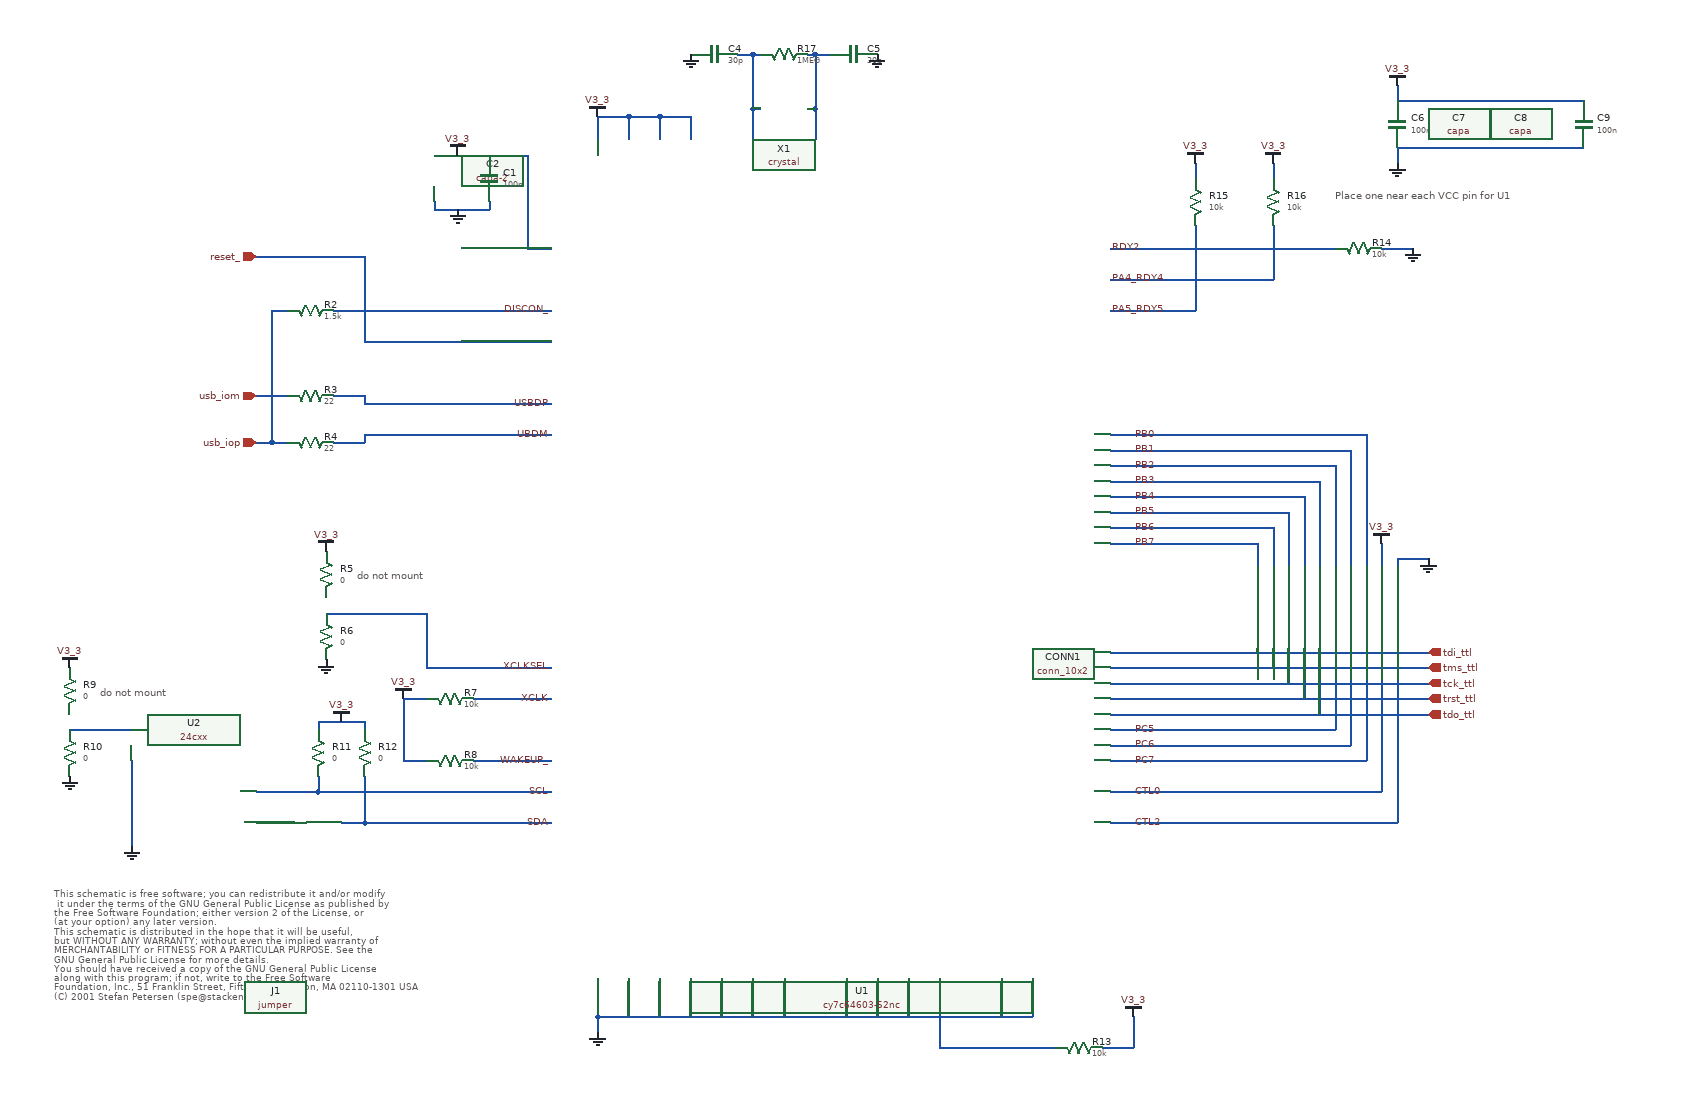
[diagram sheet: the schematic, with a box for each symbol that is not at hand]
v {xschem version=2.9.5_RC6 file_version=1.1}
G {}
V {}
S {}
E {}
T {do not mount} 410 -720 0 0 0.4 0.4 {}
T {do not mount} 80 -570 0 0 0.4 0.4 {}
T {This schematic is free software; you can redistribute it and/or modify
 it under the terms of the GNU General Public License as published by
the Free Software Foundation; either version 2 of the License, or
(at your option) any later version.
This schematic is distributed in the hope that it will be useful,
but WITHOUT ANY WARRANTY; without even the implied warranty of
MERCHANTABILITY or FITNESS FOR A PARTICULAR PURPOSE.  See the
GNU General Public License for more details.
You should have received a copy of the GNU General Public License
along with this program; if not, write to the Free Software
Foundation, Inc., 51 Franklin Street, Fifth Floor, Boston, MA 02110-1301 USA
(C) 2001 Stefan Petersen (spe@stacken.kth.se)
} 20 -310 0 0 0.3 0.3 {}
T {Place one near each VCC pin for U1} 1670 -1210 0 0 0.4 0.4 {}
N 840 -1300 840 -1270 {lab=V3_3}
N 800 -1300 840 -1300 {lab=V3_3}
N 720 -1300 720 -1270 {lab=V3_3}
N 760 -1300 760 -1270 {lab=V3_3}
N 800 -1300 800 -1270 {lab=V3_3}
N 1000 -1310 1000 -1270 {lab=#net1}
N 920 -1310 920 -1270 {lab=#net2}
N 990 -1310 1000 -1310 {lab=#net1}
N 920 -1310 930 -1310 {lab=#net2}
N 920 -1380 930 -1380 {lab=#net2}
N 1000 -1380 1020 -1380 {lab=#net1}
N 370 -660 500 -660 {lab=XCLKSEL}
N 500 -660 500 -590 {lab=XCLKSEL}
N 500 -590 660 -590 {lab=XCLKSEL}
N 560 -470 660 -470 {lab=WAKEUP_}
N 560 -550 660 -550 {lab=XCLK}
N 470 -550 500 -550 {lab=V3_3}
N 470 -550 470 -470 {lab=V3_3}
N 470 -470 500 -470 {lab=V3_3}
N 360 -430 660 -430 {lab=SCL}
N 120 -470 120 -360 {lab=GND}
N 40 -510 120 -510 {lab=#net3}
N 360 -520 360 -510 {lab=V3_3}
N 360 -520 420 -520 {lab=V3_3}
N 420 -520 420 -510 {lab=V3_3}
N 360 -450 360 -430 {lab=SCL}
N 420 -450 420 -390 {lab=SDA}
N 280 -390 330 -390 {lab=#net4}
N 420 -390 660 -390 {lab=SDA}
N 300 -880 320 -880 {lab=usb_iop}
N 280 -940 320 -940 {lab=usb_iom}
N 380 -880 420 -880 {lab=UBDM}
N 420 -890 420 -880 {lab=UBDM}
N 420 -890 660 -890 {lab=UBDM}
N 380 -940 420 -940 {lab=USBDP}
N 420 -940 420 -930 {lab=USBDP}
N 420 -930 660 -930 {lab=USBDP}
N 380 -1050 660 -1050 {lab=DISCON_}
N 300 -1050 320 -1050 {lab=usb_iop}
N 300 -1050 300 -880 {lab=usb_iop}
N 420 -1010 660 -1010 {lab=reset_}
N 420 -1120 420 -1010 {lab=reset_}
N 280 -1120 420 -1120 {lab=reset_}
N 630 -1130 660 -1130 {lab=V3_3}
N 630 -1250 630 -1130 {lab=V3_3}
N 510 -1250 630 -1250 {lab=V3_3}
N 510 -1190 510 -1180 {lab=GND}
N 510 -1180 580 -1180 {lab=GND}
N 580 -1190 580 -1180 {lab=GND}
N 1490 -1160 1490 -1050 {lab=PA5_RDY5}
N 1380 -1050 1490 -1050 {lab=PA5_RDY5}
N 1590 -1160 1590 -1090 {lab=PA4_RDY4}
N 1380 -1090 1590 -1090 {lab=PA4_RDY4}
N 1380 -1130 1670 -1130 {lab=RDY2}
N 1730 -1130 1770 -1130 {lab=GND}
N 1490 -1240 1490 -1220 {lab=V3_3}
N 1590 -1240 1590 -1220 {lab=V3_3}
N 1570 -750 1570 -720 {lab=PB7}
N 1380 -750 1570 -750 {lab=PB7}
N 1590 -770 1590 -720 {lab=PB6}
N 1380 -770 1590 -770 {lab=PB6}
N 1610 -790 1610 -720 {lab=PB5}
N 1380 -790 1610 -790 {lab=PB5}
N 1630 -810 1630 -720 {lab=PB4}
N 1380 -810 1630 -810 {lab=PB4}
N 1650 -830 1650 -720 {lab=PB3}
N 1380 -830 1650 -830 {lab=PB3}
N 1670 -850 1670 -720 {lab=PB2}
N 1380 -850 1670 -850 {lab=PB2}
N 1690 -870 1690 -720 {lab=PB1}
N 1380 -870 1690 -870 {lab=PB1}
N 1710 -890 1710 -720 {lab=PB0}
N 1380 -890 1710 -890 {lab=PB0}
N 1730 -750 1730 -720 {lab=V3_3}
N 1750 -730 1750 -720 {lab=GND}
N 1750 -730 1790 -730 {lab=GND}
N 1380 -610 1790 -610 {lab=tdi_ttl}
N 1380 -590 1790 -590 {lab=tms_ttl}
N 1380 -570 1790 -570 {lab=tck_ttl}
N 1380 -550 1790 -550 {lab=trst_ttl}
N 1380 -530 1790 -530 {lab=tdo_ttl}
N 1750 -660 1750 -390 {lab=CTL2}
N 1730 -660 1730 -430 {lab=CTL0}
N 1710 -660 1710 -470 {lab=PC7}
N 1690 -660 1690 -490 {lab=PC6}
N 720 -1300 760 -1300 {lab=V3_3}
N 760 -1300 800 -1300 {lab=V3_3}
N 1000 -1380 1000 -1310 {lab=#net1}
N 920 -1380 920 -1310 {lab=#net2}
N 280 -430 360 -430 {lab=SCL}
N 390 -390 420 -390 {lab=SDA}
N 280 -880 300 -880 {lab=usb_iop}
N 1380 -490 1690 -490 {lab=PC6}
N 1380 -470 1710 -470 {lab=PC7}
N 1380 -430 1730 -430 {lab=CTL0}
N 1380 -390 1750 -390 {lab=CTL2}
N 900 -1380 920 -1380 {lab=#net2}
N 990 -1380 1000 -1380 {lab=#net1}
N 1670 -660 1670 -510 {lab=PC5}
N 1380 -510 1670 -510 {lab=PC5}
N 1570 -660 1570 -610 {lab=tdi_ttl}
N 1590 -660 1590 -590 {lab=tms_ttl}
N 1610 -660 1610 -570 {lab=tck_ttl}
N 1630 -660 1630 -550 {lab=trst_ttl}
N 1650 -660 1650 -530 {lab=tdo_ttl}
N 1750 -1260 1990 -1260 {lab=GND}
N 1750 -1260 1750 -1240 {lab=GND}
N 1750 -1320 1990 -1320 {lab=V3_3}
N 1750 -1340 1750 -1320 {lab=V3_3}
N 720 -190 720 -140 {lab=GND}
N 760 -190 760 -140 {lab=GND}
N 800 -190 800 -140 {lab=GND}
N 840 -190 840 -140 {lab=GND}
N 880 -190 880 -140 {lab=GND}
N 920 -190 920 -140 {lab=GND}
N 960 -190 960 -140 {lab=GND}
N 1080 -190 1080 -140 {lab=GND}
N 1040 -190 1040 -140 {lab=GND}
N 1120 -190 1120 -140 {lab=GND}
N 1240 -190 1240 -140 {lab=GND}
N 1280 -190 1280 -140 {lab=GND}
N 720 -140 1280 -140 {lab=GND}
N 720 -140 720 -120 {lab=GND}
N 1160 -190 1160 -100 {lab=#net5}
N 1160 -100 1310 -100 {lab=#net5}
N 1370 -100 1410 -100 {lab=V3_3}
N 1410 -140 1410 -100 {lab=V3_3}
C {title.sym} 160 -30 0 0 {name=l1 author="Stefan Schippers"}
C {cy7c64603-52nc.sym} 1020 -630 0 0 {name=U1 device=cy7c64603-52nc footprint=cy7c64603_qfp}
C {vdd.sym} 720 -1300 0 0 {name=l2 lab=V3_3}
C {res.sym} 960 -1380 3 1 {name=R17
value=1MEG
footprint=1206
device=resistor
m=1}
C {crystal.sym} 960 -1310 1 0 {name=X1
value=12MHz
footprint=CRYSTAL 300
device=CRYSTAL}
C {capa.sym} 1050 -1380 3 1 {name=C5
m=1
value=30p
footprint=sm1206
device="ceramic capacitor"}
C {capa.sym} 870 -1380 1 0 {name=C4
m=1
value=30p
footprint=sm1206
device="ceramic capacitor"}
C {gnd.sym} 1080 -1380 0 0 {name=l3 lab=GND}
C {gnd.sym} 840 -1380 0 1 {name=l4 lab=GND}
C {24cxx.sym} 200 -450 0 0 {name=U2
power=V3_3
ground=GND}
C {res.sym} 370 -710 0 0 {name=R5
value=0
footprint=sm0805
device=resistor
m=1}
C {res.sym} 370 -630 0 0 {name=R6
value=0
footprint=sm0805
device=resistor
m=1}
C {noconn.sym} 370 -680 3 0 {name=l5}
C {gnd.sym} 370 -600 0 0 {name=l6 lab=GND}
C {vdd.sym} 370 -740 0 0 {name=l7 lab=V3_3}
C {res.sym} 530 -550 3 1 {name=R7
value=10k
footprint=sm0805
device=resistor
m=1}
C {noconn.sym} 660 -510 3 0 {name=l8}
C {res.sym} 530 -470 3 1 {name=R8
value=10k
footprint=sm0805
device=resistor
m=1}
C {vdd.sym} 470 -550 0 0 {name=l9 lab=V3_3}
C {noconn.sym} 280 -470 1 1 {name=l10}
C {gnd.sym} 120 -360 0 0 {name=l11 lab=GND}
C {res.sym} 40 -480 0 0 {name=R10
value=0
footprint=sm0805
device=resistor
m=1}
C {gnd.sym} 40 -450 0 0 {name=l12 lab=GND}
C {res.sym} 40 -560 0 0 {name=R9
value=0
footprint=sm0805
device=resistor
m=1}
C {noconn.sym} 40 -530 3 0 {name=l13}
C {vdd.sym} 40 -590 0 0 {name=l14 lab=V3_3}
C {res.sym} 420 -480 0 0 {name=R12
value=0
footprint=sm0805
device=resistor
m=1}
C {res.sym} 360 -480 0 0 {name=R11
value=0
footprint=sm0805
device=resistor
m=1}
C {vdd.sym} 390 -520 0 0 {name=l15 lab=V3_3}
C {jumper.sym} 360 -390 1 0 {name=J1}
C {ipin.sym} 280 -940 0 0 {name=p1 lab=usb_iom}
C {ipin.sym} 280 -880 0 0 {name=p2 lab=usb_iop}
C {res.sym} 350 -940 3 1 {name=R3
value=22
footprint=sm0805
device=resistor
m=1}
C {res.sym} 350 -880 3 1 {name=R4
value=22
footprint=sm0805
device=resistor
m=1}
C {res.sym} 350 -1050 3 1 {name=R2
value=1.5k
footprint=sm0805
device=resistor
m=1}
C {ipin.sym} 280 -1120 0 0 {name=p3 lab=reset_}
C {capa-2.sym} 510 -1220 0 0 {name=C2
m=1
value=2.2u
footprint=sm1206
device="polarized_capacitor"}
C {capa.sym} 580 -1220 0 0 {name=C1
m=1
value=100n
footprint=sm1206
device="capacitor"}
C {gnd.sym} 540 -1180 0 0 {name=l16 lab=GND}
C {vdd.sym} 540 -1250 0 0 {name=l17 lab=V3_3}
C {res.sym} 1490 -1190 0 0 {name=R15
value=10k
footprint=sm0805
device=resistor
m=1}
C {res.sym} 1590 -1190 0 0 {name=R16
value=10k
footprint=sm0805
device=resistor
m=1}
C {res.sym} 1700 -1130 3 1 {name=R14
value=10k
footprint=sm0805
device=resistor
m=1}
C {gnd.sym} 1770 -1130 0 0 {name=l18 lab=GND}
C {vdd.sym} 1490 -1240 0 0 {name=l19 lab=V3_3}
C {vdd.sym} 1590 -1240 0 0 {name=l20 lab=V3_3}
C {conn_10x2.sym} 1590 -690 3 0 {name=CONN1 footprint="connector 10 2"}
C {vdd.sym} 1730 -750 0 0 {name=l21 lab=V3_3}
C {gnd.sym} 1790 -730 0 0 {name=l22 lab=GND}
C {ipin.sym} 1790 -530 0 1 {name=p4 lab=tdo_ttl}
C {opin.sym} 1790 -550 0 0 {name=p6 lab=trst_ttl}
C {opin.sym} 1790 -570 0 0 {name=p7 lab=tck_ttl}
C {opin.sym} 1790 -590 0 0 {name=p8 lab=tms_ttl}
C {opin.sym} 1790 -610 0 0 {name=p9 lab=tdi_ttl}
C {capa.sym} 1750 -1290 0 0 {name=C6
m=1
value=100n
footprint=sm1206
device="capacitor"}
C {capa.sym} 1830 -1290 0 0 {name=C7
m=1
value=100n
footprint=sm1206
device="capacitor"}
C {capa.sym} 1910 -1290 0 0 {name=C8
m=1
value=100n
footprint=sm1206
device="capacitor"}
C {capa.sym} 1990 -1290 0 0 {name=C9
m=1
value=100n
footprint=sm1206
device="capacitor"}
C {vdd.sym} 1750 -1340 0 0 {name=l23 lab=V3_3}
C {gnd.sym} 1750 -1240 0 0 {name=l24 lab=GND}
C {gnd.sym} 720 -120 0 0 {name=l25 lab=GND}
C {noconn.sym} 1200 -190 3 0 {name=l26}
C {res.sym} 1340 -100 3 1 {name=R13
value=10k
footprint=sm0805
device=resistor
m=1}
C {vdd.sym} 1410 -140 0 0 {name=l27 lab=V3_3}
C {lab_wire.sym} 1410 -890 0 1 {name=p5 lab=PB0}
C {lab_wire.sym} 1410 -870 0 1 {name=p10 lab=PB1}
C {lab_wire.sym} 1410 -850 0 1 {name=p11 lab=PB2}
C {lab_wire.sym} 1410 -830 0 1 {name=p12 lab=PB3}
C {lab_wire.sym} 1410 -810 0 1 {name=p13 lab=PB4}
C {lab_wire.sym} 1410 -790 0 1 {name=p14 lab=PB5}
C {lab_wire.sym} 1410 -770 0 1 {name=p15 lab=PB6}
C {lab_wire.sym} 1410 -750 0 1 {name=p16 lab=PB7}
C {lab_wire.sym} 1410 -510 0 1 {name=p22 lab=PC5}
C {lab_wire.sym} 1410 -490 0 1 {name=p23 lab=PC6}
C {lab_wire.sym} 1410 -470 0 1 {name=p24 lab=PC7}
C {lab_wire.sym} 1410 -430 0 1 {name=p25 lab=CTL0}
C {lab_wire.sym} 1410 -390 0 1 {name=p26 lab=CTL2}
C {lab_wire.sym} 660 -1050 0 0 {name=p27 lab=DISCON_}
C {lab_wire.sym} 660 -930 0 0 {name=p29 lab=USBDP}
C {lab_wire.sym} 660 -890 0 0 {name=p30 lab=UBDM}
C {lab_wire.sym} 660 -590 0 0 {name=p31 lab=XCLKSEL}
C {lab_wire.sym} 660 -550 0 0 {name=p32 lab=XCLK}
C {lab_wire.sym} 660 -470 0 0 {name=p34 lab=WAKEUP_}
C {lab_wire.sym} 660 -430 0 0 {name=p35 lab=SCL}
C {lab_wire.sym} 660 -390 0 0 {name=p36 lab=SDA}
C {lab_wire.sym} 1380 -1130 0 1 {name=p17 lab=RDY2}
C {lab_wire.sym} 1380 -1090 0 1 {name=p18 lab=PA4_RDY4}
C {lab_wire.sym} 1380 -1050 0 1 {name=p19 lab=PA5_RDY5}
